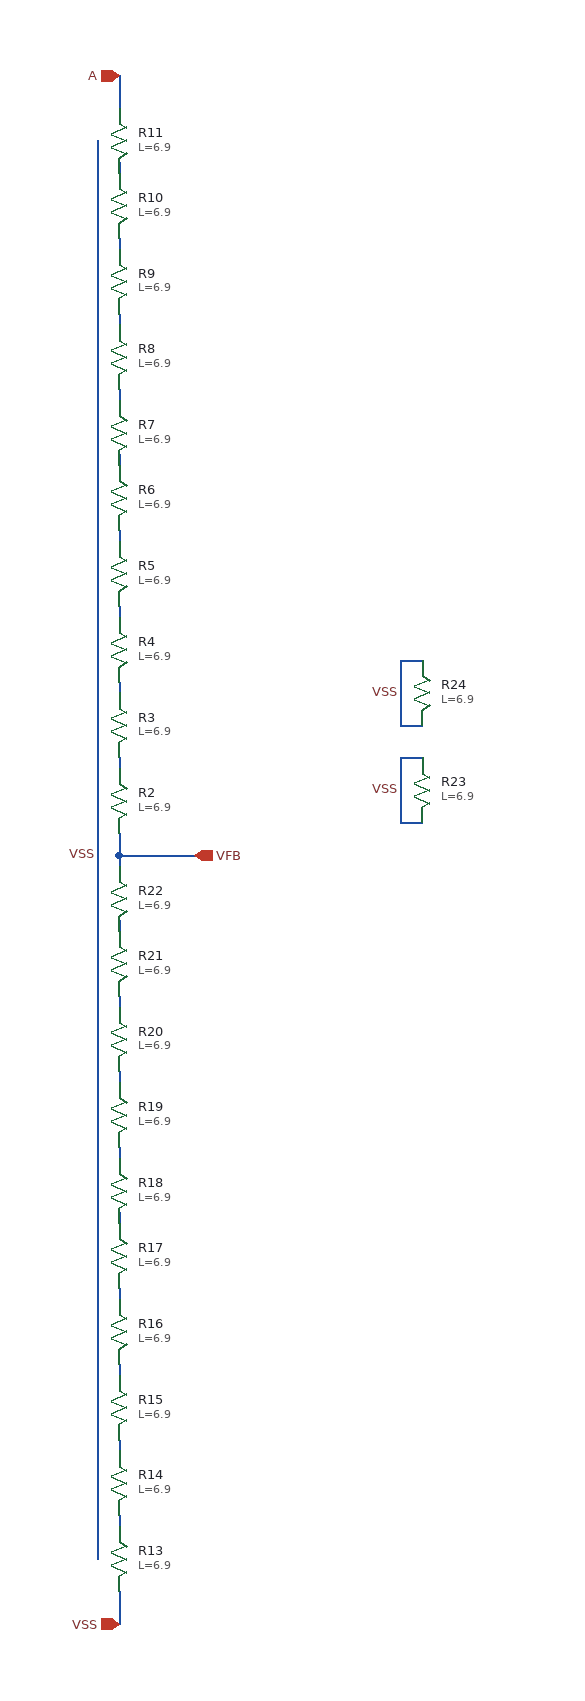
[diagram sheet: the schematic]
v {xschem version=3.4.7 file_version=1.2}
G {}
K {}
V {}
S {}
E {}
N 480 -820 480 -810 {lab=#net1}
N 480 -890 480 -880 {lab=#net2}
N 480 -960 480 -950 {lab=#net3}
N 480 -1030 480 -1020 {lab=#net4}
N 480 -1100 480 -1090 {lab=#net5}
N 480 -1160 480 -1150 {lab=#net6}
N 480 -1230 480 -1220 {lab=#net7}
N 480 -1300 480 -1290 {lab=#net8}
N 480 -1370 480 -1360 {lab=#net9}
N 480 -1430 480 -1420 {lab=A}
N 480 -120 480 -110 {lab=#net10}
N 480 -190 480 -180 {lab=#net11}
N 480 -260 480 -250 {lab=#net12}
N 480 -330 480 -320 {lab=#net13}
N 480 -400 480 -390 {lab=#net14}
N 480 -460 480 -450 {lab=#net15}
N 480 -530 480 -520 {lab=#net16}
N 480 -600 480 -590 {lab=#net17}
N 480 -670 480 -660 {lab=#net18}
N 480 -730 480 -720 {lab=VFB}
N 480 -750 480 -730 {lab=VFB}
N 460 -1390 460 -80 {lab=VSS}
N 480 -50 480 -20 {lab=VSS}
N 480 -1450 480 -1430 {lab=A}
N 480 -730 550 -730 {lab=VFB}
N 740 -820 760 -820 {lab=VSS}
N 740 -820 740 -760 {lab=VSS}
N 740 -760 760 -760 {lab=VSS}
N 740 -910 760 -910 {lab=VSS}
N 740 -910 740 -850 {lab=VSS}
N 740 -850 760 -850 {lab=VSS}
C {sky130_fd_pr/res_xhigh_po_0p69.sym} 480 -780 0 0 {name=R2
L=6.9
model=res_xhigh_po_0p69
spiceprefix=X
mult=1}
C {sky130_fd_pr/res_xhigh_po_0p69.sym} 480 -850 0 0 {name=R3
L=6.9
model=res_xhigh_po_0p69
spiceprefix=X
mult=1}
C {sky130_fd_pr/res_xhigh_po_0p69.sym} 480 -920 0 0 {name=R4
L=6.9
model=res_xhigh_po_0p69
spiceprefix=X
mult=1}
C {sky130_fd_pr/res_xhigh_po_0p69.sym} 480 -990 0 0 {name=R5
L=6.9
model=res_xhigh_po_0p69
spiceprefix=X
mult=1}
C {sky130_fd_pr/res_xhigh_po_0p69.sym} 480 -1060 0 0 {name=R6
L=6.9
model=res_xhigh_po_0p69
spiceprefix=X
mult=1}
C {sky130_fd_pr/res_xhigh_po_0p69.sym} 480 -1120 0 0 {name=R7
L=6.9
model=res_xhigh_po_0p69
spiceprefix=X
mult=1}
C {sky130_fd_pr/res_xhigh_po_0p69.sym} 480 -1190 0 0 {name=R8
L=6.9
model=res_xhigh_po_0p69
spiceprefix=X
mult=1}
C {sky130_fd_pr/res_xhigh_po_0p69.sym} 480 -1260 0 0 {name=R9
L=6.9
model=res_xhigh_po_0p69
spiceprefix=X
mult=1}
C {sky130_fd_pr/res_xhigh_po_0p69.sym} 480 -1330 0 0 {name=R10
L=6.9
model=res_xhigh_po_0p69
spiceprefix=X
mult=1}
C {sky130_fd_pr/res_xhigh_po_0p69.sym} 480 -1390 0 0 {name=R11
L=6.9
model=res_xhigh_po_0p69
spiceprefix=X
mult=1}
C {sky130_fd_pr/res_xhigh_po_0p69.sym} 480 -80 0 0 {name=R13
L=6.9
model=res_xhigh_po_0p69
spiceprefix=X
mult=1}
C {sky130_fd_pr/res_xhigh_po_0p69.sym} 480 -150 0 0 {name=R14
L=6.9
model=res_xhigh_po_0p69
spiceprefix=X
mult=1}
C {sky130_fd_pr/res_xhigh_po_0p69.sym} 480 -220 0 0 {name=R15
L=6.9
model=res_xhigh_po_0p69
spiceprefix=X
mult=1}
C {sky130_fd_pr/res_xhigh_po_0p69.sym} 480 -290 0 0 {name=R16
L=6.9
model=res_xhigh_po_0p69
spiceprefix=X
mult=1}
C {sky130_fd_pr/res_xhigh_po_0p69.sym} 480 -360 0 0 {name=R17
L=6.9
model=res_xhigh_po_0p69
spiceprefix=X
mult=1}
C {sky130_fd_pr/res_xhigh_po_0p69.sym} 480 -420 0 0 {name=R18
L=6.9
model=res_xhigh_po_0p69
spiceprefix=X
mult=1}
C {sky130_fd_pr/res_xhigh_po_0p69.sym} 480 -490 0 0 {name=R19
L=6.9
model=res_xhigh_po_0p69
spiceprefix=X
mult=1}
C {sky130_fd_pr/res_xhigh_po_0p69.sym} 480 -560 0 0 {name=R20
L=6.9
model=res_xhigh_po_0p69
spiceprefix=X
mult=1}
C {sky130_fd_pr/res_xhigh_po_0p69.sym} 480 -630 0 0 {name=R21
L=6.9
model=res_xhigh_po_0p69
spiceprefix=X
mult=1}
C {sky130_fd_pr/res_xhigh_po_0p69.sym} 480 -690 0 0 {name=R22
L=6.9
model=res_xhigh_po_0p69
spiceprefix=X
mult=1}
C {iopin.sym} 480 -20 0 0 {name=p1 lab=VSS}
C {iopin.sym} 480 -1450 0 0 {name=p2 lab=A}
C {lab_pin.sym} 460 -730 0 0 {name=p3 lab=VSS}
C {opin.sym} 550 -730 0 0 {name=p4 lab=VFB}
C {sky130_fd_pr/res_xhigh_po_0p69.sym} 760 -790 0 0 {name=R23
L=6.9
model=res_xhigh_po_0p69
spiceprefix=X
mult=1}
C {lab_pin.sym} 740 -790 0 0 {name=p5 lab=VSS}
C {sky130_fd_pr/res_xhigh_po_0p69.sym} 760 -880 0 0 {name=R24
L=6.9
model=res_xhigh_po_0p69
spiceprefix=X
mult=1}
C {lab_pin.sym} 740 -880 0 0 {name=p6 lab=VSS}
